VERSION 5.7 ;
  NAMESCASESENSITIVE ON ;
  NOWIREEXTENSIONATPIN ON ;
  DIVIDERCHAR "/" ;
  BUSBITCHARS "[]" ;
UNITS
  DATABASE MICRONS 200 ;
END UNITS

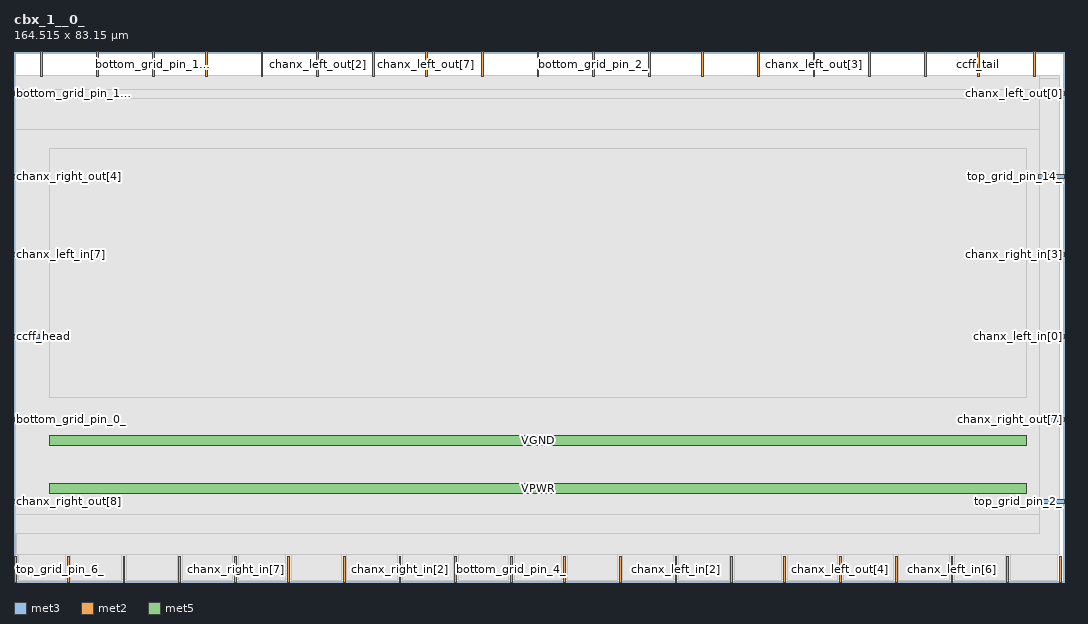
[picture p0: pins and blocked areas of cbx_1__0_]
MACRO cbx_1__0_
  CLASS BLOCK ;
  FOREIGN cbx_1__0_ ;
  ORIGIN 0.000 0.000 ;
  SIZE 164.515 BY 83.150 ;
  PIN bottom_grid_pin_0_
    DIRECTION OUTPUT TRISTATE ;
    PORT
      LAYER met3 ;
        RECT 0.000 25.200 4.000 25.800 ;
    END
  END bottom_grid_pin_0_
  PIN bottom_grid_pin_10_
    DIRECTION OUTPUT TRISTATE ;
    PORT
      LAYER met2 ;
        RECT 38.730 79.150 39.010 83.150 ;
    END
  END bottom_grid_pin_10_
  PIN bottom_grid_pin_12_
    DIRECTION OUTPUT TRISTATE ;
    PORT
      LAYER met2 ;
        RECT 21.710 79.150 21.990 83.150 ;
    END
  END bottom_grid_pin_12_
  PIN bottom_grid_pin_14_
    DIRECTION OUTPUT TRISTATE ;
    PORT
      LAYER met3 ;
        RECT 0.000 76.200 4.000 76.800 ;
    END
  END bottom_grid_pin_14_
  PIN bottom_grid_pin_2_
    DIRECTION OUTPUT TRISTATE ;
    PORT
      LAYER met2 ;
        RECT 90.710 79.150 90.990 83.150 ;
    END
  END bottom_grid_pin_2_
  PIN bottom_grid_pin_4_
    DIRECTION OUTPUT TRISTATE ;
    PORT
      LAYER met2 ;
        RECT 77.830 0.000 78.110 4.000 ;
    END
  END bottom_grid_pin_4_
  PIN bottom_grid_pin_6_
    DIRECTION OUTPUT TRISTATE ;
    PORT
      LAYER met2 ;
        RECT 94.850 0.000 95.130 4.000 ;
    END
  END bottom_grid_pin_6_
  PIN bottom_grid_pin_8_
    DIRECTION OUTPUT TRISTATE ;
    PORT
      LAYER met2 ;
        RECT 73.230 79.150 73.510 83.150 ;
    END
  END bottom_grid_pin_8_
  PIN ccff_head
    DIRECTION INPUT ;
    PORT
      LAYER met3 ;
        RECT 0.000 38.120 4.000 38.720 ;
    END
  END ccff_head
  PIN ccff_tail
    DIRECTION OUTPUT TRISTATE ;
    PORT
      LAYER met2 ;
        RECT 150.970 79.150 151.250 83.150 ;
    END
  END ccff_tail
  PIN chanx_left_in[0]
    DIRECTION INPUT ;
    PORT
      LAYER met3 ;
        RECT 160.515 38.120 164.515 38.720 ;
    END
  END chanx_left_in[0]
  PIN chanx_left_in[1]
    DIRECTION INPUT ;
    PORT
      LAYER met2 ;
        RECT 12.970 79.150 13.250 83.150 ;
    END
  END chanx_left_in[1]
  PIN chanx_left_in[2]
    DIRECTION INPUT ;
    PORT
      LAYER met2 ;
        RECT 103.590 0.000 103.870 4.000 ;
    END
  END chanx_left_in[2]
  PIN chanx_left_in[3]
    DIRECTION INPUT ;
    PORT
      LAYER met2 ;
        RECT 29.990 79.150 30.270 83.150 ;
    END
  END chanx_left_in[3]
  PIN chanx_left_in[4]
    DIRECTION INPUT ;
    PORT
      LAYER met2 ;
        RECT 99.450 79.150 99.730 83.150 ;
    END
  END chanx_left_in[4]
  PIN chanx_left_in[5]
    DIRECTION INPUT ;
    PORT
      LAYER met2 ;
        RECT 17.110 0.000 17.390 4.000 ;
    END
  END chanx_left_in[5]
  PIN chanx_left_in[6]
    DIRECTION INPUT ;
    PORT
      LAYER met2 ;
        RECT 146.830 0.000 147.110 4.000 ;
    END
  END chanx_left_in[6]
  PIN chanx_left_in[7]
    DIRECTION INPUT ;
    PORT
      LAYER met3 ;
        RECT 0.000 51.040 4.000 51.640 ;
    END
  END chanx_left_in[7]
  PIN chanx_left_in[8]
    DIRECTION INPUT ;
    PORT
      LAYER met2 ;
        RECT 163.850 0.000 164.130 4.000 ;
    END
  END chanx_left_in[8]
  PIN chanx_left_out[0]
    DIRECTION OUTPUT TRISTATE ;
    PORT
      LAYER met3 ;
        RECT 160.515 76.200 164.515 76.800 ;
    END
  END chanx_left_out[0]
  PIN chanx_left_out[1]
    DIRECTION OUTPUT TRISTATE ;
    PORT
      LAYER met2 ;
        RECT 138.090 0.000 138.370 4.000 ;
    END
  END chanx_left_out[1]
  PIN chanx_left_out[2]
    DIRECTION OUTPUT TRISTATE ;
    PORT
      LAYER met2 ;
        RECT 47.470 79.150 47.750 83.150 ;
    END
  END chanx_left_out[2]
  PIN chanx_left_out[3]
    DIRECTION OUTPUT TRISTATE ;
    PORT
      LAYER met2 ;
        RECT 125.210 79.150 125.490 83.150 ;
    END
  END chanx_left_out[3]
  PIN chanx_left_out[4]
    DIRECTION OUTPUT TRISTATE ;
    PORT
      LAYER met2 ;
        RECT 129.350 0.000 129.630 4.000 ;
    END
  END chanx_left_out[4]
  PIN chanx_left_out[5]
    DIRECTION OUTPUT TRISTATE ;
    PORT
      LAYER met2 ;
        RECT 81.970 79.150 82.250 83.150 ;
    END
  END chanx_left_out[5]
  PIN chanx_left_out[6]
    DIRECTION OUTPUT TRISTATE ;
    PORT
      LAYER met2 ;
        RECT 42.870 0.000 43.150 4.000 ;
    END
  END chanx_left_out[6]
  PIN chanx_left_out[7]
    DIRECTION OUTPUT TRISTATE ;
    PORT
      LAYER met2 ;
        RECT 64.490 79.150 64.770 83.150 ;
    END
  END chanx_left_out[7]
  PIN chanx_left_out[8]
    DIRECTION OUTPUT TRISTATE ;
    PORT
      LAYER met2 ;
        RECT 120.610 0.000 120.890 4.000 ;
    END
  END chanx_left_out[8]
  PIN chanx_right_in[0]
    DIRECTION INPUT ;
    PORT
      LAYER met2 ;
        RECT 142.690 79.150 142.970 83.150 ;
    END
  END chanx_right_in[0]
  PIN chanx_right_in[1]
    DIRECTION INPUT ;
    PORT
      LAYER met2 ;
        RECT 4.230 79.150 4.510 83.150 ;
    END
  END chanx_right_in[1]
  PIN chanx_right_in[2]
    DIRECTION INPUT ;
    PORT
      LAYER met2 ;
        RECT 60.350 0.000 60.630 4.000 ;
    END
  END chanx_right_in[2]
  PIN chanx_right_in[3]
    DIRECTION INPUT ;
    PORT
      LAYER met3 ;
        RECT 160.515 51.040 164.515 51.640 ;
    END
  END chanx_right_in[3]
  PIN chanx_right_in[4]
    DIRECTION INPUT ;
    PORT
      LAYER met2 ;
        RECT 133.950 79.150 134.230 83.150 ;
    END
  END chanx_right_in[4]
  PIN chanx_right_in[5]
    DIRECTION INPUT ;
    PORT
      LAYER met2 ;
        RECT 159.710 79.150 159.990 83.150 ;
    END
  END chanx_right_in[5]
  PIN chanx_right_in[6]
    DIRECTION INPUT ;
    PORT
      LAYER met2 ;
        RECT 155.570 0.000 155.850 4.000 ;
    END
  END chanx_right_in[6]
  PIN chanx_right_in[7]
    DIRECTION INPUT ;
    PORT
      LAYER met2 ;
        RECT 34.590 0.000 34.870 4.000 ;
    END
  END chanx_right_in[7]
  PIN chanx_right_in[8]
    DIRECTION INPUT ;
    PORT
      LAYER met2 ;
        RECT 25.850 0.000 26.130 4.000 ;
    END
  END chanx_right_in[8]
  PIN chanx_right_out[0]
    DIRECTION OUTPUT TRISTATE ;
    PORT
      LAYER met2 ;
        RECT 112.330 0.000 112.610 4.000 ;
    END
  END chanx_right_out[0]
  PIN chanx_right_out[1]
    DIRECTION OUTPUT TRISTATE ;
    PORT
      LAYER met2 ;
        RECT 86.110 0.000 86.390 4.000 ;
    END
  END chanx_right_out[1]
  PIN chanx_right_out[2]
    DIRECTION OUTPUT TRISTATE ;
    PORT
      LAYER met2 ;
        RECT 69.090 0.000 69.370 4.000 ;
    END
  END chanx_right_out[2]
  PIN chanx_right_out[3]
    DIRECTION OUTPUT TRISTATE ;
    PORT
      LAYER met2 ;
        RECT 51.610 0.000 51.890 4.000 ;
    END
  END chanx_right_out[3]
  PIN chanx_right_out[4]
    DIRECTION OUTPUT TRISTATE ;
    PORT
      LAYER met3 ;
        RECT 0.000 63.280 4.000 63.880 ;
    END
  END chanx_right_out[4]
  PIN chanx_right_out[5]
    DIRECTION OUTPUT TRISTATE ;
    PORT
      LAYER met2 ;
        RECT 8.370 0.000 8.650 4.000 ;
    END
  END chanx_right_out[5]
  PIN chanx_right_out[6]
    DIRECTION OUTPUT TRISTATE ;
    PORT
      LAYER met2 ;
        RECT 107.730 79.150 108.010 83.150 ;
    END
  END chanx_right_out[6]
  PIN chanx_right_out[7]
    DIRECTION OUTPUT TRISTATE ;
    PORT
      LAYER met3 ;
        RECT 160.515 25.200 164.515 25.800 ;
    END
  END chanx_right_out[7]
  PIN chanx_right_out[8]
    DIRECTION OUTPUT TRISTATE ;
    PORT
      LAYER met3 ;
        RECT 0.000 12.280 4.000 12.880 ;
    END
  END chanx_right_out[8]
  PIN pReset
    DIRECTION INPUT ;
    PORT
      LAYER met2 ;
        RECT 56.210 79.150 56.490 83.150 ;
    END
  END pReset
  PIN prog_clk
    DIRECTION INPUT ;
    PORT
      LAYER met2 ;
        RECT 116.470 79.150 116.750 83.150 ;
    END
  END prog_clk
  PIN top_grid_pin_14_
    DIRECTION OUTPUT TRISTATE ;
    PORT
      LAYER met3 ;
        RECT 160.515 63.280 164.515 63.880 ;
    END
  END top_grid_pin_14_
  PIN top_grid_pin_2_
    DIRECTION OUTPUT TRISTATE ;
    PORT
      LAYER met3 ;
        RECT 160.515 12.280 164.515 12.880 ;
    END
  END top_grid_pin_2_
  PIN top_grid_pin_6_
    DIRECTION OUTPUT TRISTATE ;
    PORT
      LAYER met2 ;
        RECT 0.090 0.000 0.370 4.000 ;
    END
  END top_grid_pin_6_
  PIN VPWR
    DIRECTION INPUT ;
    USE POWER ;
    PORT
      LAYER met5 ;
        RECT 5.520 13.840 158.700 15.440 ;
    END
  END VPWR
  PIN VGND
    DIRECTION INPUT ;
    USE GROUND ;
    PORT
      LAYER met5 ;
        RECT 5.520 21.340 158.700 22.940 ;
    END
  END VGND
  OBS
      LAYER li1 ;
        RECT 5.520 10.795 158.700 70.805 ;
      LAYER met1 ;
        RECT 0.530 0.380 162.310 79.180 ;
      LAYER met2 ;
        RECT 0.370 78.870 3.950 79.405 ;
        RECT 4.790 78.870 12.690 79.405 ;
        RECT 13.530 78.870 21.430 79.405 ;
        RECT 22.270 78.870 29.710 79.405 ;
        RECT 30.550 78.870 38.450 79.405 ;
        RECT 39.290 78.870 47.190 79.405 ;
        RECT 48.030 78.870 55.930 79.405 ;
        RECT 56.770 78.870 64.210 79.405 ;
        RECT 65.050 78.870 72.950 79.405 ;
        RECT 73.790 78.870 81.690 79.405 ;
        RECT 82.530 78.870 90.430 79.405 ;
        RECT 91.270 78.870 99.170 79.405 ;
        RECT 100.010 78.870 107.450 79.405 ;
        RECT 108.290 78.870 116.190 79.405 ;
        RECT 117.030 78.870 124.930 79.405 ;
        RECT 125.770 78.870 133.670 79.405 ;
        RECT 134.510 78.870 142.410 79.405 ;
        RECT 143.250 78.870 150.690 79.405 ;
        RECT 151.530 78.870 159.430 79.405 ;
        RECT 160.270 78.870 163.850 79.405 ;
        RECT 0.370 4.280 163.850 78.870 ;
        RECT 0.650 0.270 8.090 4.280 ;
        RECT 8.930 0.270 16.830 4.280 ;
        RECT 17.670 0.270 25.570 4.280 ;
        RECT 26.410 0.270 34.310 4.280 ;
        RECT 35.150 0.270 42.590 4.280 ;
        RECT 43.430 0.270 51.330 4.280 ;
        RECT 52.170 0.270 60.070 4.280 ;
        RECT 60.910 0.270 68.810 4.280 ;
        RECT 69.650 0.270 77.550 4.280 ;
        RECT 78.390 0.270 85.830 4.280 ;
        RECT 86.670 0.270 94.570 4.280 ;
        RECT 95.410 0.270 103.310 4.280 ;
        RECT 104.150 0.270 112.050 4.280 ;
        RECT 112.890 0.270 120.330 4.280 ;
        RECT 121.170 0.270 129.070 4.280 ;
        RECT 129.910 0.270 137.810 4.280 ;
        RECT 138.650 0.270 146.550 4.280 ;
        RECT 147.390 0.270 155.290 4.280 ;
        RECT 156.130 0.270 163.570 4.280 ;
      LAYER met3 ;
        RECT 0.270 77.200 160.730 79.385 ;
        RECT 4.400 75.800 160.115 77.200 ;
        RECT 0.270 64.280 160.730 75.800 ;
        RECT 4.400 62.880 160.115 64.280 ;
        RECT 0.270 52.040 160.730 62.880 ;
        RECT 4.400 50.640 160.115 52.040 ;
        RECT 0.270 39.120 160.730 50.640 ;
        RECT 4.400 37.720 160.115 39.120 ;
        RECT 0.270 26.200 160.730 37.720 ;
        RECT 4.400 24.800 160.115 26.200 ;
        RECT 0.270 13.280 160.730 24.800 ;
        RECT 4.400 11.880 160.115 13.280 ;
        RECT 0.270 7.655 160.730 11.880 ;
      LAYER met4 ;
        RECT 0.295 10.640 160.705 70.960 ;
      LAYER met5 ;
        RECT 5.520 28.840 158.700 67.940 ;
  END
END cbx_1__0_
END LIBRARY

